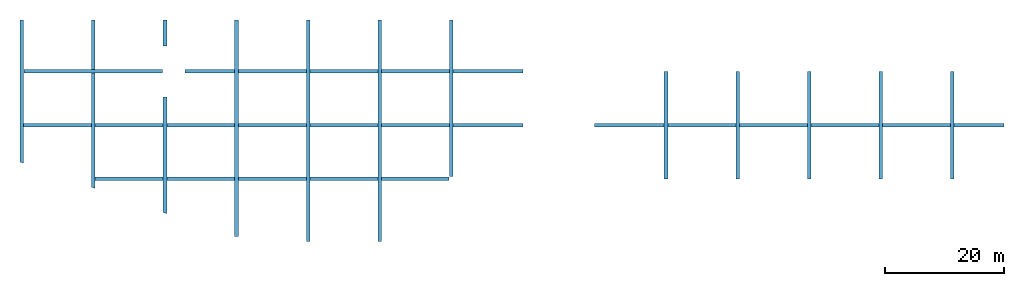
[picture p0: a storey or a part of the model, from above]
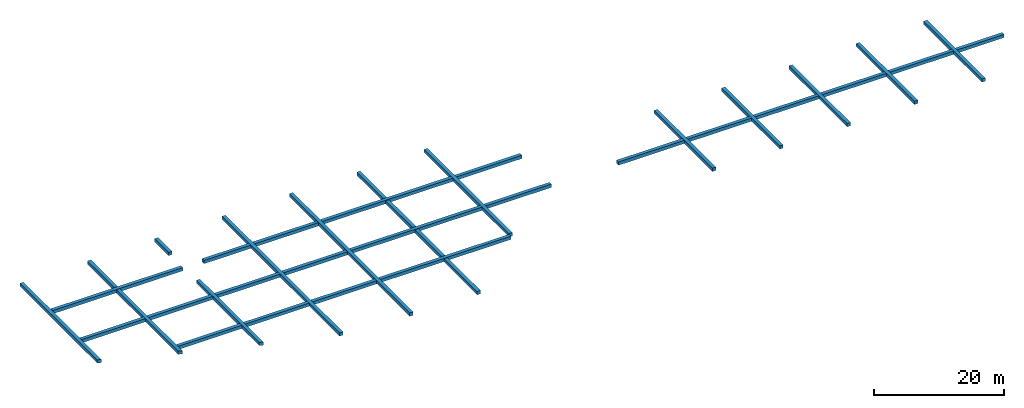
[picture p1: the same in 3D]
Properties of the parts of a building model (IFC2X3)

# File
Time: 2010-07-21T19:19:58
Written by: v1
Made in: Scia Engineer 2008.1

# IfcBeam (844)
Name | In | Material
Column351 | FL4-FRM | A992
Column352 | FL4-FRM | A992
Column353 | FL4-FRM | A992
Column354 | FL4-FRM | A992
B11 | FL4-FRM | A992
B12 | FL4-FRM | A992
B13 | FL4-FRM | A992
Column355 | FL4-FRM | A992
Column356 | FL4-FRM | A992
Column357 | FL4-FRM | A992
Column358 | FL4-FRM | A992
B19 | FL4-FRM | A992
B20 | FL4-FRM | A992
B21 | FL4-FRM | A992
B22 | FL4-FRM | A992
B23 | FL4-FRM | A992
B24 | FL4-FRM | A992
Column361 | FL4-FRM | A992
B51 | FL1-FRM | C4000
B99 | FL2-FRM | C4000
B100 | FL2-FRM | C4000
B118 | FL2-FRM | C4000
B128 | FL2-FRM | C4000
B129 | FL2-FRM | C4000
B134 | FL2-FRM | C4000
Column377 | FL4-FRM | A992
B174 | FL4-FRM | A992
B175 | FL4-FRM | A992
B176 | FL4-FRM | A992
B177 | FL4-FRM | A992
Column378 | FL4-FRM | A992
Column379 | FL4-FRM | A992
Column380 | FL4-FRM | A992
Column381 | FL4-FRM | A992
Column382 | FL4-FRM | A992
B179 | FL4-FRM | A992
B180 | FL4-FRM | A992
B181 | FL4-FRM | A992
B182 | FL4-FRM | A992
B183 | FL4-FRM | A992
B184 | FL4-FRM | A992
B185 | FL4-FRM | A992
B186 | FL4-FRM | A992
B187 | FL4-FRM | A992
B188 | FL4-FRM | A992
B189 | FL4-FRM | A992
B190 | FL4-FRM | A992
B191 | FL4-FRM | A992
B192 | FL4-FRM | A992
B193 | FL4-FRM | A992
B194 | FL4-FRM | A992
B195 | FL4-FRM | A992
B196 | FL4-FRM | A992
Column383 | FL4-FRM | A992
B198 | FL4-FRM | A992
B199 | FL4-FRM | A992
B200 | FL4-FRM | A992
B201 | FL4-FRM | A992
B202 | FL4-FRM | A992
B203 | FL4-FRM | A992
B204 | FL4-FRM | A992
Column384 | FL4-FRM | A992
Column385 | FL4-FRM | A992
B205 | FL4-FRM | A992
B207 | FL4-FRM | A992
B208 | FL4-FRM | A992
B210 | FL4-FRM | A992
B211 | FL4-FRM | A992
B212 | FL4-FRM | A992
B213 | FL4-FRM | A992
Column386 | FL4-FRM | A992
Column387 | FL4-FRM | A992
Column388 | FL4-FRM | A992
B214 | FL4-FRM | A992
B215 | FL4-FRM | A992
B216 | FL4-FRM | A992
B217 | FL4-FRM | A992
B218 | FL4-FRM | A992
B219 | FL4-FRM | A992
B220 | FL4-FRM | A992
B221 | FL4-FRM | A992
Column389 | FL4-FRM | A992
Column390 | FL4-FRM | A992
Column391 | FL4-FRM | A992
B222 | FL4-FRM | A992
B223 | FL4-FRM | A992
B224 | FL4-FRM | A992
B225 | FL4-FRM | A992
B226 | FL4-FRM | A992
B227 | FL4-FRM | A992
B228 | FL4-FRM | A992
B229 | FL4-FRM | A992
Column392 | FL4-FRM | A992
Column393 | FL4-FRM | A992
Column394 | FL4-FRM | A992
B234 | FL4-FRM | A992
B235 | FL4-FRM | A992
B236 | FL4-FRM | A992
B237 | FL4-FRM | A992
Column395 | FL4-FRM | A992
Column396 | FL4-FRM | A992
Column397 | FL4-FRM | A992
B242 | FL4-FRM | A992
B243 | FL4-FRM | A992
B245 | FL4-FRM | A992
Column398 | FL4-FRM | A992
Column400 | FL4-FRM | A992
Column401 | FL5-FRM | A992
Column402 | FL5-FRM | A992
B252 | FL5-FRM | A992
B253 | FL5-FRM | A992
B254 | FL5-FRM | A992
B255 | FL5-FRM | A992
B256 | FL5-FRM | A992
Column403 | FL5-FRM | A992
Column404 | FL5-FRM | A992
B257 | FL5-FRM | A992
B258 | FL5-FRM | A992
B259 | FL5-FRM | A992
Column405 | FL5-FRM | A992
B260 | FL5-FRM | A992
Column406 | FL5-FRM | A992
B261 | FL5-FRM | A992
B262 | FL5-FRM | A992
B263 | FL5-FRM | A992
Column407 | FL5-FRM | A992
B264 | FL5-FRM | A992
Column408 | FL5-FRM | A992
B265 | FL5-FRM | A992
B266 | FL5-FRM | A992
B267 | FL5-FRM | A992
B268 | FL5-FRM | A992
B269 | FL5-FRM | A992
B270 | FL5-FRM | A992
Column409 | FL5-FRM | A992
Column411 | FL5-FRM | A992
B276 | FL5-FRM | A992
B278 | FL5-FRM | A992
Column412 | FL5-FRM | A992
Column413 | FL5-FRM | A992
Column414 | FL5-FRM | A992
Column415 | FL5-FRM | A992
B280 | FL5-FRM | A992
B281 | FL5-FRM | A992
B282 | FL5-FRM | A992
B283 | FL5-FRM | A992
B284 | FL5-FRM | A992
B285 | FL5-FRM | A992
B286 | FL5-FRM | A992
B287 | FL5-FRM | A992
B288 | FL5-FRM | A992
B289 | FL5-FRM | A992
B290 | FL5-FRM | A992
B291 | FL5-FRM | A992
B292 | FL5-FRM | A992
B293 | FL5-FRM | A992
B294 | FL5-FRM | A992
B295 | FL5-FRM | A992
B296 | FL5-FRM | A992
B297 | FL5-FRM | A992
Column435 | FL6-FRM | A992
Column436 | FL6-FRM | A992
B353 | FL6-FRM | A992
B354 | FL6-FRM | A992
B355 | FL6-FRM | A992
B356 | FL6-FRM | A992
B357 | FL6-FRM | A992
Column437 | FL6-FRM | A992
Column438 | FL6-FRM | A992
B358 | FL6-FRM | A992
B359 | FL6-FRM | A992
B360 | FL6-FRM | A992
Column439 | FL6-FRM | A992
B361 | FL6-FRM | A992
Column440 | FL6-FRM | A992
B362 | FL6-FRM | A992
B363 | FL6-FRM | A992
B364 | FL6-FRM | A992
Column441 | FL6-FRM | A992
B365 | FL6-FRM | A992
Column442 | FL6-FRM | A992
B366 | FL6-FRM | A992
B367 | FL6-FRM | A992
B368 | FL6-FRM | A992
B369 | FL6-FRM | A992
B370 | FL6-FRM | A992
B371 | FL6-FRM | A992
B372 | FL6-FRM | A992
Column443 | FL6-FRM | A992
Column446 | FL6-FRM | A992
Column447 | FL6-FRM | A992
Column448 | FL6-FRM | A992
Column449 | FL6-FRM | A992
Column450 | FL6-FRM | A992
B377 | FL6-FRM | A992
B378 | FL6-FRM | A992
B379 | FL6-FRM | A992
B380 | FL6-FRM | A992
B381 | FL6-FRM | A992
B382 | FL6-FRM | A992
B383 | FL6-FRM | A992
B384 | FL6-FRM | A992
B385 | FL6-FRM | A992
B386 | FL6-FRM | A992
B387 | FL6-FRM | A992
B388 | FL6-FRM | A992
B389 | FL6-FRM | A992
B390 | FL6-FRM | A992
B391 | FL6-FRM | A992
B392 | FL6-FRM | A992
B393 | FL6-FRM | A992
B394 | FL6-FRM | A992
B395 | FL6-FRM | A992
Column453 | FL3-FRM | A992
Column454 | FL3-FRM | A992
Column455 | FL3-FRM | A992
Column456 | FL3-FRM | A992
B405 | FL3-FRM | A992
B406 | FL3-FRM | A992
B407 | FL3-FRM | A992
Column457 | FL3-FRM | A992
Column458 | FL3-FRM | A992
Column459 | FL3-FRM | A992
Column460 | FL3-FRM | A992
B413 | FL3-FRM | A992
B414 | FL3-FRM | A992
B415 | FL3-FRM | A992
B416 | FL3-FRM | A992
B417 | FL3-FRM | A992
B418 | FL3-FRM | A992
Column461 | FL3-FRM | A992
Column463 | FL3-FRM | A992
B424 | FL3-FRM | A992
B426 | FL3-FRM | A992
Column464 | FL3-FRM | A992
Column465 | FL3-FRM | A992
Column466 | FL3-FRM | A992
Column467 | FL3-FRM | A992
B428 | FL3-FRM | A992
B429 | FL3-FRM | A992
B430 | FL3-FRM | A992
B431 | FL3-FRM | A992
B432 | FL3-FRM | A992
B433 | FL3-FRM | A992
B434 | FL3-FRM | A992
B435 | FL3-FRM | A992
B436 | FL3-FRM | A992
B437 | FL3-FRM | A992
B438 | FL3-FRM | A992
B439 | FL3-FRM | A992
B440 | FL3-FRM | A992
B441 | FL3-FRM | A992
B442 | FL3-FRM | A992
B443 | FL3-FRM | A992
B444 | FL3-FRM | A992
B445 | FL3-FRM | A992
Column469 | FL3-FRM | A992
B447 | FL3-FRM | A992
B448 | FL3-FRM | A992
B449 | FL3-FRM | A992
B450 | FL3-FRM | A992
B451 | FL3-FRM | A992
B452 | FL3-FRM | A992
B453 | FL3-FRM | A992
Column470 | FL3-FRM | A992
Column471 | FL3-FRM | A992
B454 | FL3-FRM | A992
B456 | FL3-FRM | A992
B457 | FL3-FRM | A992
B459 | FL3-FRM | A992
B460 | FL3-FRM | A992
B461 | FL3-FRM | A992
B462 | FL3-FRM | A992
Column472 | FL3-FRM | A992
Column473 | FL3-FRM | A992
Column474 | FL3-FRM | A992
B463 | FL3-FRM | A992
B464 | FL3-FRM | A992
B465 | FL3-FRM | A992
B466 | FL3-FRM | A992
B467 | FL3-FRM | A992
B468 | FL3-FRM | A992
B469 | FL3-FRM | A992
B470 | FL3-FRM | A992
Column475 | FL3-FRM | A992
Column476 | FL3-FRM | A992
Column477 | FL3-FRM | A992
B471 | FL3-FRM | A992
B472 | FL3-FRM | A992
B473 | FL3-FRM | A992
B474 | FL3-FRM | A992
B475 | FL3-FRM | A992
B476 | FL3-FRM | A992
B477 | FL3-FRM | A992
B478 | FL3-FRM | A992
Column478 | FL3-FRM | A992
Column479 | FL3-FRM | A992
Column480 | FL3-FRM | A992
B483 | FL3-FRM | A992
B484 | FL3-FRM | A992
B485 | FL3-FRM | A992
B486 | FL3-FRM | A992
Column481 | FL3-FRM | A992
Column482 | FL3-FRM | A992
Column483 | FL3-FRM | A992
B494 | FL3-FRM | A992
Column484 | FL3-FRM | A992
Column486 | FL3-FRM | A992
Column489 | FL2-FRM | A992
B501 | FL2-FRM | A992
B502 | FL2-FRM | A992
B503 | FL2-FRM | A992
B504 | FL2-FRM | A992
B506 | FL2-FRM | A992
B507 | FL2-FRM | A992
B508 | FL2-FRM | A992
B509 | FL2-FRM | A992
B510 | FL2-FRM | A992
B511 | FL2-FRM | A992
B512 | FL2-FRM | A992
B513 | FL2-FRM | A992
B514 | FL2-FRM | A992
B515 | FL2-FRM | A992
B516 | FL2-FRM | A992
B517 | FL2-FRM | A992
B518 | FL2-FRM | A992
B519 | FL2-FRM | A992
B523 | FL2-FRM | A992
B524 | FL2-FRM | A992
B525 | FL2-FRM | A992
B526 | FL2-FRM | A992
B527 | FL2-FRM | A992
B529 | FL2-FRM | A992
B530 | FL2-FRM | A992
B531 | FL2-FRM | A992
B532 | FL2-FRM | A992
B533 | FL2-FRM | A992
B534 | FL2-FRM | A992
B535 | FL2-FRM | A992
B536 | FL2-FRM | A992
B537 | FL2-FRM | A992
B538 | FL2-FRM | A992
Column490 | FL2-FRM | A992
Column492 | FL2-FRM | A992
Column493 | FL2-FRM | A992
Column494 | FL2-FRM | A992
Column495 | FL2-FRM | A992
Column496 | FL2-FRM | A992
Column497 | FL2-FRM | A992
Column498 | FL2-FRM | A992
Column499 | FL2-FRM | A992
Column500 | FL2-FRM | A992
Column501 | FL2-FRM | A992
Column502 | FL2-FRM | A992
Column503 | FL2-FRM | A992
Column504 | FL2-FRM | A992
B551 | FL6-FRM | A992
B552 | FL6-FRM | A992
B553 | FL6-FRM | A992
Column509 | FL2-FRM | A992
Column510 | FL2-FRM | A992
B580 | FL2-FRM | A992
Column511 | FL2-FRM | A992
B582 | FL2-FRM | A992
B583 | FL2-FRM | A992
B593 | FL3-FRM | A992
B595 | FL3-FRM | A992
B596 | FL3-FRM | A992
B599 | FL2-FRM | A992
B607 | FL5-FRM | A992
B608 | FL5-FRM | A992
B609 | FL2-FRM | A992
B680 | FL1-FRM | C4000
B681 | FL1-FRM | C4000
B683 | FL1-FRM | C4000
B684 | FL1-FRM | C4000
B685 | FL1-FRM | C4000
B686 | FL1-FRM | C4000
B687 | FL1-FRM | C4000
B688 | FL1-FRM | C4000
B689 | FL1-FRM | C4000
B690 | FL1-FRM | C4000
B705 | FL2-FRM | C4000
B706 | FL2-FRM | C4000
B707 | FL2-FRM | C4000
B713 | FL2-FRM | C4000
B714 | FL2-FRM | C4000
B715 | FL2-FRM | C4000
B716 | FL2-FRM | C4000
B717 | FL2-FRM | C4000
B746 | FL6-FRM | A992
B747 | FL3-FRM | A992
B750 | FL2-FRM | A992
B751 | FL2-FRM | A992
B752 | FL4-FRM | A992
B753 | FL4-FRM | A992
B754 | FL4-FRM | A992
B755 | FL5-FRM | A992
B756 | FL5-FRM | A992
Column570 | FL5-FRM | A992
B757 | FL6-FRM | A992
B758 | FL3-FRM | A992
B761 | FL5-FRM | A992
B762 | FL3-FRM | A992
B763 | FL2-FRM | A992
B778 | FL2-FRM | C4000
B779 | FL2-FRM | C4000
B780 | FL2-FRM | C4000
B787 | FL1-FRM | C4000
B800 | FL2-FRM | A992
B801 | FL5-FRM | A992
Column582 | FL5-FRM | A992
B802 | FL5-FRM | A992
B803 | FL5-FRM | A992
B804 | FL5-FRM | A992
B805 | FL5-FRM | A992
B806 | FL5-FRM | A992
B807 | FL5-FRM | A992
B808 | FL5-FRM | A992
Column583 | FL5-FRM | A992
Column584 | FL5-FRM | A992
B809 | FL5-FRM | A992
B811 | FL5-FRM | A992
B812 | FL5-FRM | A992
B813 | FL5-FRM | A992
B814 | FL5-FRM | A992
B815 | FL5-FRM | A992
B816 | FL5-FRM | A992
Column585 | FL5-FRM | A992
Column586 | FL5-FRM | A992
Column587 | FL5-FRM | A992
B817 | FL5-FRM | A992
B818 | FL5-FRM | A992
B819 | FL5-FRM | A992
B820 | FL5-FRM | A992
B821 | FL5-FRM | A992
B822 | FL5-FRM | A992
B823 | FL5-FRM | A992
B824 | FL5-FRM | A992
Column588 | FL5-FRM | A992
Column589 | FL5-FRM | A992
Column590 | FL5-FRM | A992
B825 | FL5-FRM | A992
B826 | FL5-FRM | A992
B827 | FL5-FRM | A992
B828 | FL5-FRM | A992
B829 | FL5-FRM | A992
B830 | FL5-FRM | A992
B831 | FL5-FRM | A992
B832 | FL5-FRM | A992
Column591 | FL5-FRM | A992
Column592 | FL5-FRM | A992
Column593 | FL5-FRM | A992
B837 | FL5-FRM | A992
B838 | FL5-FRM | A992
B839 | FL5-FRM | A992
B840 | FL5-FRM | A992
Column594 | FL5-FRM | A992
Column595 | FL5-FRM | A992
Column596 | FL5-FRM | A992
B845 | FL5-FRM | A992
B846 | FL5-FRM | A992
B847 | FL5-FRM | A992
B848 | FL5-FRM | A992
Column597 | FL5-FRM | A992
Column598 | FL5-FRM | A992
Column599 | FL5-FRM | A992
Column600 | FL6-FRM | A992
B855 | FL6-FRM | A992
B856 | FL6-FRM | A992
B857 | FL6-FRM | A992
B858 | FL6-FRM | A992
B859 | FL6-FRM | A992
B860 | FL6-FRM | A992
B861 | FL6-FRM | A992
Column601 | FL6-FRM | A992
Column602 | FL6-FRM | A992
B862 | FL6-FRM | A992
B864 | FL6-FRM | A992
B865 | FL6-FRM | A992
B866 | FL6-FRM | A992
B867 | FL6-FRM | A992
B868 | FL6-FRM | A992
B869 | FL6-FRM | A992
Column603 | FL6-FRM | A992
Column604 | FL6-FRM | A992
Column605 | FL6-FRM | A992
B870 | FL6-FRM | A992
B871 | FL6-FRM | A992
B872 | FL6-FRM | A992
B873 | FL6-FRM | A992
B874 | FL6-FRM | A992
B875 | FL6-FRM | A992
B876 | FL6-FRM | A992
B877 | FL6-FRM | A992
Column606 | FL6-FRM | A992
Column607 | FL6-FRM | A992
Column608 | FL6-FRM | A992
B878 | FL6-FRM | A992
B879 | FL6-FRM | A992
B880 | FL6-FRM | A992
B881 | FL6-FRM | A992
B882 | FL6-FRM | A992
B883 | FL6-FRM | A992
B884 | FL6-FRM | A992
B885 | FL6-FRM | A992
Column609 | FL6-FRM | A992
Column610 | FL6-FRM | A992
Column611 | FL6-FRM | A992
B886 | FL6-FRM | A992
B887 | FL6-FRM | A992
B888 | FL6-FRM | A992
B889 | FL6-FRM | A992
B890 | FL6-FRM | A992
B891 | FL6-FRM | A992
B892 | FL6-FRM | A992
B893 | FL6-FRM | A992
Column612 | FL6-FRM | A992
Column613 | FL6-FRM | A992
Column614 | FL6-FRM | A992
B896 | FL6-FRM | A992
B898 | FL6-FRM | A992
B899 | FL6-FRM | A992
B900 | FL6-FRM | A992
B901 | FL6-FRM | A992
Column615 | FL6-FRM | A992
Column616 | FL6-FRM | A992
Column617 | FL6-FRM | A992
B905 | FL6-FRM | A992
B908 | FL6-FRM | A992
B909 | FL6-FRM | A992
B910 | FL6-FRM | A992
B911 | FL6-FRM | A992
B912 | FL6-FRM | A992
B913 | FL6-FRM | A992
B914 | FL6-FRM | A992
B915 | FL6-FRM | A992
B916 | FL6-FRM | A992
B917 | FL6-FRM | A992
B918 | FL6-FRM | A992
B919 | FL6-FRM | A992
B920 | FL6-FRM | A992
B921 | FL6-FRM | A992
B922 | FL6-FRM | A992
B923 | FL6-FRM | A992
B924 | FL6-FRM | A992
B925 | FL6-FRM | A992
B927 | FL6-FRM | A992
B928 | FL6-FRM | A992
B929 | FL6-FRM | A992
B930 | FL6-FRM | A992
B931 | FL6-FRM | A992
Column618 | FL6-FRM | A992
B932 | FL5-FRM | A992
B933 | FL5-FRM | A992
B934 | FL5-FRM | A992
B935 | FL5-FRM | A992
B936 | FL5-FRM | A992
B937 | FL5-FRM | A992
B938 | FL5-FRM | A992
B939 | FL5-FRM | A992
B940 | FL5-FRM | A992
B941 | FL5-FRM | A992
B942 | FL5-FRM | A992
B943 | FL5-FRM | A992
B944 | FL5-FRM | A992
B945 | FL5-FRM | A992
B946 | FL5-FRM | A992
B947 | FL5-FRM | A992
B948 | FL5-FRM | A992
B949 | FL5-FRM | A992
B950 | FL5-FRM | A992
B951 | FL5-FRM | A992
B952 | FL5-FRM | A992
B953 | FL5-FRM | A992
B954 | FL5-FRM | A992
B955 | FL5-FRM | A992
B956 | FL5-FRM | A992
B957 | FL5-FRM | A992
B958 | FL5-FRM | A992
Column619 | FL5-FRM | A992
B959 | FL5-FRM | A992
B960 | FL5-FRM | A992
B961 | FL5-FRM | A992
B962 | FL5-FRM | A992
B963 | FL5-FRM | A992
B964 | FL5-FRM | A992
B965 | FL5-FRM | A992
B966 | FL5-FRM | A992
B967 | FL5-FRM | A992
B968 | FL5-FRM | A992
B969 | FL5-FRM | A992
B970 | FL5-FRM | A992
B971 | FL5-FRM | A992
B972 | FL5-FRM | A992
B973 | FL5-FRM | A992
B974 | FL5-FRM | A992
B975 | FL5-FRM | A992
B976 | FL5-FRM | A992
B977 | FL5-FRM | A992
B978 | FL5-FRM | A992
B979 | FL4-FRM | A992
B980 | FL4-FRM | A992
B981 | FL4-FRM | A992
B982 | FL4-FRM | A992
B983 | FL4-FRM | A992
B984 | FL4-FRM | A992
B985 | FL4-FRM | A992
B986 | FL4-FRM | A992
B987 | FL4-FRM | A992
B988 | FL4-FRM | A992
B989 | FL4-FRM | A992
B990 | FL4-FRM | A992
B991 | FL4-FRM | A992
B992 | FL4-FRM | A992
B993 | FL4-FRM | A992
B994 | FL4-FRM | A992
B995 | FL4-FRM | A992
B996 | FL4-FRM | A992
B997 | FL4-FRM | A992
B998 | FL4-FRM | A992
B999 | FL4-FRM | A992
B1000 | FL4-FRM | A992
B1001 | FL4-FRM | A992
B1002 | FL4-FRM | A992
B1003 | FL4-FRM | A992
B1004 | FL4-FRM | A992
B1005 | FL4-FRM | A992
B1006 | FL4-FRM | A992
B1007 | FL4-FRM | A992
B1008 | FL4-FRM | A992
B1009 | FL4-FRM | A992
B1010 | FL4-FRM | A992
B1011 | FL4-FRM | A992
B1012 | FL4-FRM | A992
B1013 | FL4-FRM | A992
B1014 | FL4-FRM | A992
B1015 | FL4-FRM | A992
B1016 | FL4-FRM | A992
B1017 | FL4-FRM | A992
B1018 | FL4-FRM | A992
B1019 | FL4-FRM | A992
B1020 | FL4-FRM | A992
B1021 | FL4-FRM | A992
B1022 | FL4-FRM | A992
B1023 | FL4-FRM | A992
B1024 | FL4-FRM | A992
B1025 | FL4-FRM | A992
B1026 | FL4-FRM | A992
B1027 | FL4-FRM | A992
B1028 | FL4-FRM | A992
B1029 | FL4-FRM | A992
B1030 | FL4-FRM | A992
Column620 | FL4-FRM | A992
B1031 | FL4-FRM | A992
B1032 | FL4-FRM | A992
Column621 | FL4-FRM | A992
B1033 | FL4-FRM | A992
B1034 | FL4-FRM | A992
B1035 | FL4-FRM | A992
B1036 | FL4-FRM | A992
B1037 | FL3-FRM | A992
B1038 | FL3-FRM | A992
B1039 | FL3-FRM | A992
B1040 | FL3-FRM | A992
B1041 | FL3-FRM | A992
B1042 | FL3-FRM | A992
B1043 | FL3-FRM | A992
Column622 | FL3-FRM | A992
B1044 | FL3-FRM | A992
B1045 | FL3-FRM | A992
B1046 | FL3-FRM | A992
B1047 | FL3-FRM | A992
B1048 | FL3-FRM | A992
B1049 | FL3-FRM | A992
B1050 | FL3-FRM | A992
B1051 | FL3-FRM | A992
B1052 | FL3-FRM | A992
B1053 | FL3-FRM | A992
B1054 | FL3-FRM | A992
B1055 | FL3-FRM | A992
B1056 | FL3-FRM | A992
B1057 | FL3-FRM | A992
B1058 | FL3-FRM | A992
B1059 | FL3-FRM | A992
B1060 | FL3-FRM | A992
B1061 | FL3-FRM | A992
B1062 | FL3-FRM | A992
B1063 | FL3-FRM | A992
B1064 | FL3-FRM | A992
B1065 | FL3-FRM | A992
B1066 | FL3-FRM | A992
B1067 | FL3-FRM | A992
B1068 | FL3-FRM | A992
B1069 | FL3-FRM | A992
B1070 | FL3-FRM | A992
B1071 | FL3-FRM | A992
B1072 | FL3-FRM | A992
B1073 | FL3-FRM | A992
B1074 | FL3-FRM | A992
B1075 | FL3-FRM | A992
B1076 | FL3-FRM | A992
B1077 | FL3-FRM | A992
B1078 | FL3-FRM | A992
B1079 | FL3-FRM | A992
B1080 | FL3-FRM | A992
B1081 | FL3-FRM | A992
B1082 | FL3-FRM | A992
B1083 | FL3-FRM | A992
B1084 | FL3-FRM | A992
B1085 | FL3-FRM | A992
B1086 | FL3-FRM | A992
B1087 | FL3-FRM | A992
B1088 | FL3-FRM | A992
B1089 | FL3-FRM | A992
B1090 | FL3-FRM | A992
B1091 | FL3-FRM | A992
Column623 | FL3-FRM | A992
B1092 | FL3-FRM | A992
B1093 | FL3-FRM | A992
B1094 | FL3-FRM | A992
B1095 | FL3-FRM | A992
B1096 | FL2-FRM | A992
B1097 | FL2-FRM | A992
B1098 | FL2-FRM | A992
B1099 | FL2-FRM | A992
B1100 | FL2-FRM | A992
B1101 | FL2-FRM | A992
B1102 | FL2-FRM | A992
B1103 | FL2-FRM | A992
B1104 | FL2-FRM | A992
B1105 | FL2-FRM | A992
B1106 | FL2-FRM | A992
B1107 | FL2-FRM | A992
B1108 | FL2-FRM | A992
B1109 | FL2-FRM | A992
Column644 | FL2-FRM | A992
B1125 | ROF-FRM | A992
B1126 | ROF-FRM | A992
B1127 | ROF-FRM | A992
B1128 | ROF-FRM | A992
B1129 | ROF-FRM | A992
B1130 | ROF-FRM | A992
B1131 | ROF-FRM | A992
B1132 | ROF-FRM | A992
B1133 | ROF-FRM | A992
B1134 | ROF-FRM | A992
B1135 | ROF-FRM | A992
B1136 | ROF-FRM | A992
B1137 | ROF-FRM | A992
B1138 | ROF-FRM | A992
B1139 | ROF-FRM | A992
B1140 | ROF-FRM | A992
B1141 | ROF-FRM | A992
B1142 | ROF-FRM | A992
B1143 | ROF-FRM | A992
B1144 | ROF-FRM | A992
B1145 | ROF-FRM | A992
B1146 | ROF-FRM | A992
B1147 | ROF-FRM | A992
B1149 | ROF-FRM | A992
B1150 | ROF-FRM | A992
B1151 | ROF-FRM | A992
B1152 | ROF-FRM | A992
B1153 | ROF-FRM | A992
B1154 | ROF-FRM | A992
B1155 | ROF-FRM | A992
B1156 | ROF-FRM | A992
B1157 | ROF-FRM | A992
B1158 | ROF-FRM | A992
B1159 | ROF-FRM | A992
B1161 | ROF-FRM | A992
B1162 | ROF-FRM | A992
B1163 | ROF-FRM | A992
B1164 | ROF-FRM | A992
B1165 | ROF-FRM | A992
B1166 | ROF-FRM | A992
B1167 | ROF-FRM | A992
B1168 | ROF-FRM | A992
B1169 | ROF-FRM | A992
B1170 | ROF-FRM | A992
B1171 | ROF-FRM | A992
B1172 | ROF-FRM | A992
B1173 | ROF-FRM | A992
B1174 | ROF-FRM | A992
B1175 | ROF-FRM | A992
B1176 | ROF-FRM | A992
B1177 | ROF-FRM | A992
B1178 | ROF-FRM | A992
B1160 | ROF-FRM | A992
B1188 | ROF-FRM | A992
B1179 | ROF-FRM | A992
B1180 | ROF-FRM | A992
B1181 | ROF-FRM | A992
B1182 | FL6-FRM | A992
B1184 | FL6-FRM | A992
B1185 | FL6-FRM | A992
B1186 | ROF-FRM | A992
B1187 | ROF-FRM | A992
B1189 | FL3-FRM | A992
B1190 | FL4-FRM | A992
B1192 | FL2-FRM | C4000
B1193 | FL2-FRM | C4000
B1195 | FL2-FRM | C4000
B1196 | FL2-FRM | C4000
B1197 | FL2-FRM | C4000
B1198 | FL2-FRM | C4000
B1199 | FL2-FRM | C4000
B1211 | FL1-FRM | C4000
B1212 | FL1-FRM | C4000
B1213 | FL1-FRM | C4000
B1214 | FL1-FRM | C4000
B1215 | FL1-FRM | C4000
B1216 | FL1-FRM | C4000
B1217 | FL2-FRM | C4000
B1218 | FL2-FRM | C4000
B1219 | FL2-FRM | C4000
B1220 | FL2-FRM | C4000
B1221 | FL2-FRM | C4000
B1222 | FL3-FRM | A992
B1223 | FL6-FRM | A500 grade B
B1224 | FL6-FRM | A500 grade B
B1225 | FL6-FRM | A500 grade B
B1226 | FL6-FRM | A500 grade B
B1227 | FL4-FRM | A500 grade B
B1228 | FL4-FRM | A500 grade B
B1229 | FL4-FRM | A500 grade B
B1230 | FL4-FRM | A500 grade B
B1231 | FL2-FRM | A500 grade B
B1232 | FL2-FRM | A500 grade B
B1233 | FL2-FRM | A500 grade B
B1234 | FL2-FRM | A500 grade B
B1235 | FL6-FRM | A992
B1238 | FL5-FRM | A992
B1239 | FL5-FRM | A992
B1240 | FL4-FRM | A992
B1241 | FL4-FRM | A992
B1242 | FL3-FRM | A992
B1243 | FL3-FRM | A992
B1244 | FL2-FRM | A992
B1245 | FL2-FRM | A992
B1246 | FL6-FRM | A992
B1247 | FL6-FRM | A992
B1248 | FL6-FRM | A992

# IfcColumn (175)
Name | In | Material
Column46 | FL5-FRM | A992
Column172 | FL2-FRM | C5000
Column173 | FL2-FRM | C5000
Column174 | FL2-FRM | C5000
Column175 | FL2-FRM | C5000
Column176 | FL2-FRM | C5000
Column177 | FL2-FRM | C5000
Column178 | FL2-FRM | C5000
Column179 | FL2-FRM | C5000
Column180 | FL2-FRM | C5000
Column203 | FL2-FRM | C5000
Column204 | FL2-FRM | C5000
Column205 | FL2-FRM | C5000
Column206 | FL2-FRM | C5000
Column214 | B1-FRM | C5000
Column215 | B1-FRM | C5000
Column247 | B1-FRM | C5000
Column255 | B1-FRM | C5000
Column256 | B1-FRM | C5000
Column257 | B1-FRM | C5000
Column258 | B1-FRM | C5000
Column259 | B1-FRM | C5000
Column273 | FL5-FRM | A992
Column274 | FL2-FRM | A992
Column275 | FL5-FRM | A992
Column276 | FL2-FRM | A992
Column277 | FL5-FRM | A992
Column278 | FL2-FRM | A992
Column279 | FL5-FRM | A992
Column280 | FL2-FRM | A992
Column281 | FL5-FRM | A992
Column282 | FL2-FRM | A992
Column283 | FL5-FRM | A992
Column284 | FL2-FRM | A992
Column285 | FL5-FRM | A992
Column286 | FL2-FRM | A992
Column287 | FL5-FRM | A992
Column288 | FL2-FRM | A992
Column289 | FL5-FRM | A992
Column290 | FL2-FRM | A992
Column291 | FL5-FRM | A992
Column292 | FL2-FRM | A992
Column293 | FL5-FRM | A992
Column294 | FL2-FRM | A992
Column295 | FL5-FRM | A992
Column296 | FL2-FRM | A992
Column297 | FL5-FRM | A992
Column298 | FL2-FRM | A992
Column299 | FL4-FRM | A992
Column301 | FL4-FRM | A992
Column303 | FL4-FRM | A992
Column305 | FL4-FRM | A992
Column307 | FL4-FRM | A992
Column309 | FL4-FRM | A992
Column311 | FL4-FRM | A992
Column313 | FL4-FRM | A992
Column315 | FL4-FRM | A992
Column317 | FL4-FRM | A992
Column319 | FL4-FRM | A992
Column321 | FL4-FRM | A992
Column323 | FL4-FRM | A992
Column325 | FL4-FRM | A992
Column327 | FL4-FRM | A992
Column331 | FL4-FRM | A992
Column332 | FL2-FRM | A992
Column334 | FL5-FRM | A992
Column337 | FL2-FRM | A500 grade B
Column339 | FL2-FRM | A992
Column341 | FL2-FRM | A500 grade B
Column343 | FL2-FRM | A992
Column345 | FL2-FRM | A992
B27 | B1-FRM | C5000
B28 | B1-FRM | C5000
B29 | B1-FRM | C5000
B30 | B1-FRM | C5000
B31 | B1-FRM | C5000
B32 | B1-FRM | C5000
B33 | B1-FRM | C5000
B34 | B1-FRM | C5000
B35 | B1-FRM | C5000
Column373 | FL2-FRM | C5000
Column521 | B1-FRM | C5000
Column522 | B1-FRM | C5000
Column523 | B1-FRM | C5000
Column524 | B1-FRM | C5000
Column526 | B1-FRM | C5000
Column527 | B1-FRM | C5000
Column528 | B1-FRM | C5000
Column529 | B1-FRM | C5000
Column530 | B1-FRM | C5000
Column531 | B1-FRM | C5000
Column532 | B1-FRM | C5000
Column533 | B1-FRM | C5000
Column534 | B1-FRM | C5000
Column535 | B1-FRM | C5000
Column536 | B1-FRM | C5000
Column537 | B1-FRM | C5000
Column538 | B1-FRM | C5000
Column539 | B1-FRM | C5000
Column540 | B1-FRM | C5000
Column541 | B1-FRM | C5000
Column542 | FL2-FRM | C5000
Column543 | FL2-FRM | C5000
Column544 | FL2-FRM | C5000
Column545 | FL2-FRM | C5000
Column546 | FL2-FRM | C5000
Column547 | FL2-FRM | C5000
Column548 | FL2-FRM | C5000
Column549 | FL2-FRM | C5000
Column550 | FL2-FRM | C5000
Column551 | FL2-FRM | C5000
Column552 | FL2-FRM | C5000
Column553 | FL2-FRM | C5000
Column554 | FL2-FRM | C5000
Column555 | FL2-FRM | C5000
Column556 | FL2-FRM | C5000
Column557 | FL2-FRM | C5000
Column558 | FL2-FRM | C5000
Column559 | FL2-FRM | C5000
Column560 | FL2-FRM | C5000
Column561 | FL2-FRM | C5000
Column562 | FL2-FRM | C5000
Column563 | FL2-FRM | C5000
Column564 | FL2-FRM | C5000
Column565 | FL2-FRM | C5000
Column566 | FL2-FRM | C5000
Column567 | FL2-FRM | C5000
Column568 | B1-FRM | C5000
Column569 | B1-FRM | C5000
Column571 | FL2-FRM | A992
Column572 | FL2-FRM | A992
B788 | SHRWLS | C5000
B789 | SHRWLS | C5000
B790 | SHRWLS | C5000
B791 | SHRWLS | C5000
B792 | SHRWLS | C5000
B795 | SHRWLS | C3000
B796 | SHRWLS | C3000
B797 | SHRWLS | C3000
B798 | SHRWLS | C3000
B799 | SHRWLS | C3000
Column625 | FL2-FRM | C5000
Column626 | FL2-FRM | C5000
Column627 | B1-FRM | C5000
Column628 | B1-FRM | C5000
Column634 | FL2-FRM | A992
Column635 | FL2-FRM | A992
Column638 | FL2-FRM | A992
Column639 | FL2-FRM | A992
Column640 | FL2-FRM | A992
Column641 | FL2-FRM | A992
Column642 | FL2-FRM | A992
Column643 | FL2-FRM | A992
B1119 | SHRWLS | C3000
Column645 | FL2-FRM | A992
Column646 | FL2-FRM | A992
Column647 | FL2-FRM | A992
Column648 | FL2-FRM | A992
Column649 | FL2-FRM | A992
Column650 | FL2-FRM | A992
Column651 | FL2-FRM | A992
B1120 | SHRWLS | C5000
Column652 | FL6-FRM | A992
Column653 | FL6-FRM | A992
B1122 | B1-FRM | C5000
B1123 | B1-FRM | C5000
B1124 | B1-FRM | C5000
Column654 | FL2-FRM | A992
Column655 | FL4-FRM | A992
Column656 | FL2-FRM | A992
Column657 | FL4-FRM | A992
B1210 | B1-FRM | C5000
Column658 | B1-FRM | C5000
Column659 | B1-FRM | C5000
Column660 | B1-FRM | C5000

# IfcSlab (69)
PredefinedType: FLOOR
Name | In | Material
Floor | ROF-PLT | A36
Floor2 | FL6-PLT | C4000
Floor5 | FL5-PLT | C4000
Floor8 | FL4-PLT | C4000
Floor11 | FL3-PLT | C4000
Floor18 | FL2-PLT | C4000
Floor21 | FL1-PLT | C4000
Floor22 | FL1-PLT | C4000
Floor23 | FL1-PLT | C4000
Floor24 | FL1-PLT | C4000
Floor25 | FL1-PLT | C4000
Wall70 | SHRWLS | C5000
Wall84 | SHRWLS | C5000
Wall85 | SHRWLS | C5000
Wall86 | SHRWLS | C5000
Wall93 | SHRWLS | C5000
Wall94 | SHRWLS | C5000
Wall113 | SHRWLS | C5000
Floor27 | FL2-PLT | C4000
Floor34 | FL2-PLT | C4000
Wall147 | FL1-PLT | C4000
Wall148 | FL1-PLT | C4000
Wall149 | FL1-PLT | C4000
Wall150 | SHRWLS | C4000
Floor40 | FL3-PLT | C3000
Floor42 | FL2-PLT | C3000
Wall166 | SHRWLS | C5000
Wall168 | SHRWLS | C5000
Wall169 | SHRWLS | C5000
Wall170 | B1 SLAB | C4000
Wall177 | SHRWLS | C5000
Wall179 | SHRWLS | C5000
Wall180 | SHRWLS | C5000
Floor53 | ROF-PLT | A36
Wall185 | ROF-PLT | C3000
Wall186 | ROF-PLT | C3000
Wall191 | FL5-PLT | C3000
Wall192 | FL4-PLT | C3000
Wall194 | FL5-PLT | C3000
Wall197 | FL4-PLT | C3000
Wall198 | FL2-PLT | C4000
Wall199 | FL2-PLT | C4000
Wall202 | FL6-PLT | C4000
Wall203 | SHRWLS | C5000
Wall204 | SHRWLS | C5000
Wall205 | SHRWLS | C5000
Floor56 | FL6-PLT | C3000
Floor57 | FL6-PLT | C3000
Wall206 | FL2-PLT | C3000
Wall207 | FL2-PLT | C3000
Floor58 | FL3-PLT | C3000
Floor60 | FL3-PLT | C3000
Floor61 | FL3-PLT | C3000
Wall208 | FL4-PLT | C3000
Wall209 | FL4-PLT | C3000
Wall210 | FL5-PLT | C3000
Wall211 | FL5-PLT | C3000
Floor62 | FL6-PLT | C3000
Floor63 | FL6-PLT | C3000
Wall212 | B1 SLAB | C4000
Wall213 | FL2-PLT | C4000
Wall214 | FL2-PLT | C4000
Wall215 | FL2-PLT | C4000
Wall216 | FL2-PLT | C4000
Wall217 | FL2-PLT | C4000
Wall219 | SHRWLS | C4000
Wall220 | SHRWLS | C4000
Wall221 | SHRWLS | C4000
Wall222 | SHRWLS | C4000

# IfcWall (42)
In: SHRWLS
Name | Material
Wall99 | C5000
Wall100 | C5000
Wall101 | C5000
Wall102 | C5000
Wall103 | C5000
Wall104 | C5000
Wall105 | C5000
Wall106 | C5000
Wall107 | C5000
Wall108 | C5000
Wall109 | C5000
Wall119 | C5000
Wall122 | C5000
Wall130 | C5000
Wall115 | C5000
Wall132 | C5000
Wall133 | C5000
Wall134 | C5000
Wall135 | C5000
Wall136 | C5000
Wall137 | C5000
Wall138 | C5000
Wall139 | C5000
Wall140 | C5000
Wall141 | C5000
Wall151 | C4000
Wall152 | C4000
Wall153 | C4000
Wall158 | C5000
Wall164 | C5000
Wall165 | C5000
Wall171 | C5000
Wall173 | C5000
Wall174 | C5000
Wall175 | C5000
Wall176 | C5000
Wall178 | C5000
Wall182 | C5000
Wall183 | C4000
Wall184 | C4000
Wall200 | C5000
Wall218 | C4000
